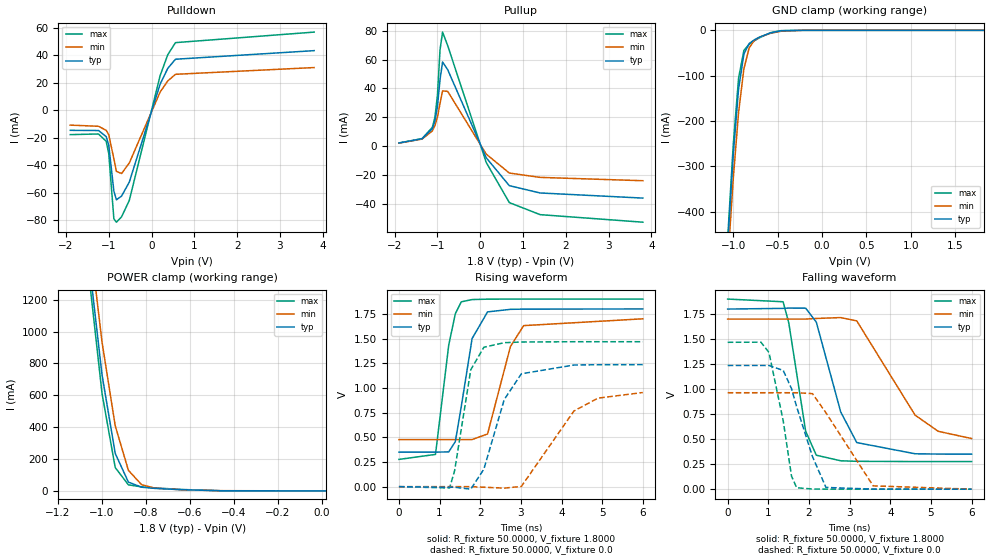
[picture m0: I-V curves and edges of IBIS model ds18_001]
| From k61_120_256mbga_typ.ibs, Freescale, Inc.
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|   Model ds18_001
[Model]  ds18_001
Model_type 3-state
Polarity   Non-Inverting
Enable   Active-High
Vmeas =  0.9000V
Cref =   5.0000pF
Rref =   50.0000
C_comp   2.8000pF   2.5000pF   3.3000pF
[Temperature Range]   25.0000   0.1250k   -40.0000
[Voltage Range]   1.8000V   1.7000V   1.9000V
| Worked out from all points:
|   slope of the pulldown table from 0 to 0.27 V, typ, clamps not added: 11.2 ohm
|   slope of the pullup table from 0 to 0.27 V, typ, clamps not added: 18.8 ohm
|   GND clamp passes 1 mA (typ) near -0.46 V on its own axis
|   POWER clamp passes 1 mA (typ) near -0.45 V on its own axis
|   rising waveform, R_fixture 50.0000, V_fixture 1.8000: 20-80 % time 332ps typ, 430ps min, 277ps max; typ from 0.35 V to 1.8 V
|   rising waveform, R_fixture 50.0000, V_fixture 0.0: 20-80 % time 570ps typ, 923ps min, 339ps max; typ from 0 V to 1.24 V
|   falling waveform, R_fixture 50.0000, V_fixture 1.8000: 20-80 % time 611ps typ, 1.01ns min, 370ps max; typ from 1.8 V to 0.35 V
|   falling waveform, R_fixture 50.0000, V_fixture 0.0: 20-80 % time 564ps typ, 819ps min, 364ps max; typ from 1.24 V to 0 V
[Pulldown]
|Voltage   I(typ)   I(min)   I(max)
-1.9V     -14.47mA   -10.68mA   -17.6mA
-1.24V    -14.61mA   -11.52mA   -17.12mA
-1.06V    -19.04mA   -14.43mA   -22.44mA
-1V       -25.15mA   -17.68mA   -31.3mA
-880mV    -58.65mA   -35.2mA    -78.83mA
-820mV    -65.02mA   -44.33mA   -81.3mA
-700mV    -62.28mA   -45.9mA    -77.39mA
-520mV    -52.15mA   -38.25mA   -65.51mA
200mV     19.05mA    13.33mA    25.2mA
380mV     30.63mA    21.47mA    40.58mA
560mV     37.26mA    26.29mA    49.33mA
3.8V      43.5mA     31.2mA     57mA
[Pullup]
|Voltage   I(typ)   I(min)   I(max)
-1.9V     2.2mA      2.1mA      2.2mA
-1.36V    5.12mA     4.89mA     5.22mA
-1.12V    12.03mA    10.51mA    13.03mA
-1.06V    17.26mA    14.11mA    19.75mA
-1V       27.56mA    20.14mA    35.27mA
-940mV    46.01mA    29.52mA    66.69mA
-880mV    58.31mA    38.3mA     79.05mA
-760mV    52.96mA    37.97mA    69.63mA
140mV     -8.043mA   -5.526mA   -11.31mA
680mV     -27.39mA   -18.63mA   -39.12mA
1.4V      -32.44mA   -21.64mA   -47.46mA
3.8V      -35.99mA   -23.95mA   -52.69mA
[GND_clamp]
|Voltage   I(typ)   I(min)   I(max)
-1.9V     -3.877A    -3.837A    -3.922A
-1.06V    -463.6mA   -508.5mA   -451.3mA
-1V       -275mA     -328.4mA   -253.5mA
-940mV    -129.7mA   -181.9mA   -105.9mA
-880mV    -52.51mA   -84.69mA   -44.33mA
-820mV    -28.99mA   -38.43mA   -30.44mA
-760mV    -20.64mA   -21.74mA   -22.76mA
-700mV    -14.74mA   -14.68mA   -15.93mA
-580mV    -5.641mA   -6.578mA   -5.151mA
-460mV    -1.036mA   -1.897mA   -614.1uA
-220mV    -1.001uA   -15.63uA   -61.01nA
1.82V     927pA      961.6nA    217.2pA
[POWER_clamp]
|Voltage   I(typ)   I(min)   I(max)
-1.9V     14.99A     14.89A     15.1A
-1.06V    1.452A     1.634A     1.361A
-1V       729.6mA    935mA      612.3mA
-940mV    235.7mA    409.7mA    146.8mA
-880mV    55.12mA    129.3mA    38.22mA
-820mV    23.43mA    39.21mA    25.26mA
-760mV    15.93mA    17.42mA    19.04mA
-640mV    7.842mA    7.361mA    9.207mA
-460mV    1.151mA    1.601mA    977.3uA
20mV      403.6pA    26.53nA    232.4pA
[Ramp]
| variable   typ   min   max
dV/dt_r  0.7416/0.5701n   0.5720/0.9232n   0.8805/0.3387n
dV/dt_f  0.8702/0.6106n   0.7164/1.0094n   0.9745/0.3696n
R_load = 50.0000
[Rising Waveform]
R_fixture= 50.0000
V_fixture= 1.8000
V_fixture_min= 1.7000
V_fixture_max= 1.9000
|time   V(typ)   V(min)   V(max)
0s        349.5mV    476.7mV    275.9mV
899.6ps   349.5mV    476.7mV    326.6mV
1.225ns   352.2mV    476.7mV    1.434V
1.387ns   456mV      476.7mV    1.751V
1.534ns   812.8mV    476.6mV    1.872V
1.8ns     1.5V       477mV      1.895V
2.18ns    1.77V      533.6mV    1.899V
2.743ns   1.796V     1.419V     1.9V
3.068ns   1.798V     1.631V     1.9V
6ns       1.8V       1.7V       1.9V
[Rising Waveform]
R_fixture= 50.0000
V_fixture= 0.0
|time   V(typ)   V(min)   V(max)
0s        4.995nV    534.5nV    1.392nV
1.246ns   -5.912mV   920.4nV    -13.49mV
1.37ns    -6.013mV   516.7nV    161.5mV
1.767ns   -25.44mV   141.7uV    1.184V
2.089ns   177.1mV    -6.003mV   1.412V
2.59ns    881.8mV    -14.79mV   1.458V
3.011ns   1.143V     2.086mV    1.465V
4.305ns   1.232V     766.3mV    1.468V
4.898ns   1.235V     896.6mV    1.468V
6ns       1.236V     953.3mV    1.468V
[Falling Waveform]
R_fixture= 50.0000
V_fixture= 1.8000
V_fixture_min= 1.7000
V_fixture_max= 1.9000
|time   V(typ)   V(min)   V(max)
0s        1.8V       1.7V       1.9V
1.364ns   1.807V     1.7V       1.873V
1.505ns   1.81V      1.7V       1.66V
1.919ns   1.809V     1.7V       579.2mV
2.181ns   1.67V      1.706V     339.4mV
2.781ns   772.2mV    1.715V     283.7mV
3.176ns   465.8mV    1.682V     278.3mV
4.611ns   353.7mV    739.9mV    275.9mV
5.179ns   350.8mV    578.4mV    275.9mV
6ns       349.7mV    506mV      275.9mV
[Falling Waveform]
R_fixture= 50.0000
V_fixture= 0.0
|time   V(typ)   V(min)   V(max)
0s        1.236V     963.9mV    1.468V
819.3ps   1.236V     963.9mV    1.469V
1.017ns   1.236V     963.9mV    1.366V
1.367ns   1.187V     963.9mV    683.1mV
1.571ns   1.005V     963.9mV    131mV
1.697ns   824.5mV    963.8mV    14.31mV
2.085ns   327.7mV    954.7mV    1.455mV
2.418ns   17.48mV    763.9mV    517.7uV
3.579ns   362uV      33mV       14.07uV
6ns       1.83uV     124.8uV    12.23nV
